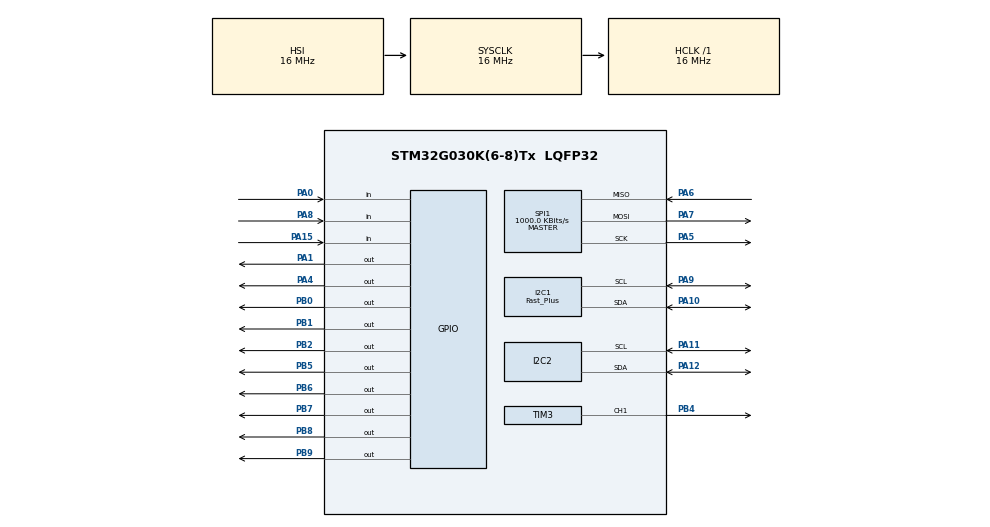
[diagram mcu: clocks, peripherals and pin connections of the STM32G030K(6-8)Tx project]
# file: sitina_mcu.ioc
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Dma.I2C1_RX.1.Direction=DMA_PERIPH_TO_MEMORY
Dma.I2C1_RX.1.EventEnable=DISABLE
Dma.I2C1_RX.1.Instance=DMA1_Channel2
Dma.I2C1_RX.1.MemDataAlignment=DMA_MDATAALIGN_BYTE
Dma.I2C1_RX.1.MemInc=DMA_MINC_ENABLE
Dma.I2C1_RX.1.Mode=DMA_NORMAL
Dma.I2C1_RX.1.PeriphDataAlignment=DMA_PDATAALIGN_BYTE
Dma.I2C1_RX.1.PeriphInc=DMA_PINC_DISABLE
Dma.I2C1_RX.1.Polarity=HAL_DMAMUX_REQ_GEN_RISING
Dma.I2C1_RX.1.Priority=DMA_PRIORITY_LOW
Dma.I2C1_RX.1.RequestNumber=1
Dma.I2C1_RX.1.SignalID=NONE
Dma.I2C1_RX.1.SyncEnable=DISABLE
Dma.I2C1_RX.1.SyncPolarity=HAL_DMAMUX_SYNC_NO_EVENT
Dma.I2C1_RX.1.SyncRequestNumber=1
Dma.I2C1_RX.1.SyncSignalID=NONE
Dma.I2C1_TX.2.Direction=DMA_MEMORY_TO_PERIPH
Dma.I2C1_TX.2.EventEnable=DISABLE
Dma.I2C1_TX.2.Instance=DMA1_Channel3
Dma.I2C1_TX.2.MemDataAlignment=DMA_MDATAALIGN_BYTE
Dma.I2C1_TX.2.MemInc=DMA_MINC_ENABLE
Dma.I2C1_TX.2.Mode=DMA_NORMAL
Dma.I2C1_TX.2.PeriphDataAlignment=DMA_PDATAALIGN_BYTE
Dma.I2C1_TX.2.PeriphInc=DMA_PINC_DISABLE
Dma.I2C1_TX.2.Polarity=HAL_DMAMUX_REQ_GEN_RISING
Dma.I2C1_TX.2.Priority=DMA_PRIORITY_LOW
Dma.I2C1_TX.2.RequestNumber=1
Dma.I2C1_TX.2.SignalID=NONE
Dma.I2C1_TX.2.SyncEnable=DISABLE
Dma.I2C1_TX.2.SyncPolarity=HAL_DMAMUX_SYNC_NO_EVENT
Dma.I2C1_TX.2.SyncRequestNumber=1
Dma.I2C1_TX.2.SyncSignalID=NONE
Dma.Request0=SPI1_TX
Dma.Request1=I2C1_RX
Dma.Request2=I2C1_TX
Dma.SPI1_TX.0.Direction=DMA_MEMORY_TO_PERIPH
Dma.SPI1_TX.0.EventEnable=DISABLE
Dma.SPI1_TX.0.Instance=DMA1_Channel1
Dma.SPI1_TX.0.MemDataAlignment=DMA_MDATAALIGN_BYTE
Dma.SPI1_TX.0.MemInc=DMA_MINC_ENABLE
Dma.SPI1_TX.0.Mode=DMA_NORMAL
Dma.SPI1_TX.0.PeriphDataAlignment=DMA_PDATAALIGN_BYTE
Dma.SPI1_TX.0.PeriphInc=DMA_PINC_DISABLE
Dma.SPI1_TX.0.Polarity=HAL_DMAMUX_REQ_GEN_RISING
Dma.SPI1_TX.0.Priority=DMA_PRIORITY_LOW
Dma.SPI1_TX.0.RequestNumber=1
Dma.SPI1_TX.0.SignalID=NONE
Dma.SPI1_TX.0.SyncEnable=DISABLE
Dma.SPI1_TX.0.SyncPolarity=HAL_DMAMUX_SYNC_NO_EVENT
Dma.SPI1_TX.0.SyncRequestNumber=1
Dma.SPI1_TX.0.SyncSignalID=NONE
I2C1.I2C_Speed_Mode=I2C_Fast_Plus
I2C1.OwnAddress=32
I2C1.Timing=0x00200105
I2C2.Timing=0x00503D58
Mcu.Family=STM32G0
Mcu.Name=STM32G030K(6-8)Tx
Mcu.Package=LQFP32
NVIC.DMA1_Channel1_IRQn=true\:0\:0\:false\:false\:true\:false\:true\:true
NVIC.DMA1_Channel2_3_IRQn=true\:0\:0\:false\:false\:true\:false\:true\:true
NVIC.I2C1_IRQn=true\:0\:0\:false\:false\:true\:true\:true\:true
NVIC.RTC_TAMP_IRQn=true\:0\:0\:false\:false\:true\:true\:true\:true
PA0.Signal=GPIO_Input
PA1.Signal=GPIO_Output
PA10.Mode=I2C
PA10.Signal=I2C1_SDA
PA11\ [PA9].Mode=I2C
PA11\ [PA9].Signal=I2C2_SCL
PA12\ [PA10].Mode=I2C
PA12\ [PA10].Signal=I2C2_SDA
PA13.Mode=Serial_Wire
PA13.Signal=SYS_SWDIO
PA14-BOOT0.Mode=Serial_Wire
PA14-BOOT0.Signal=SYS_SWCLK
PA15.Signal=GPIO_Input
PA2.Signal=USART2_TX
PA3.Signal=USART2_RX
PA4.Signal=GPIO_Output
PA5.Mode=Full_Duplex_Master
PA5.Signal=SPI1_SCK
PA6.Mode=Full_Duplex_Master
PA6.Signal=SPI1_MISO
PA7.Mode=Full_Duplex_Master
PA7.Signal=SPI1_MOSI
PA8.Signal=GPIO_Input
PA9.Mode=I2C
PA9.Signal=I2C1_SCL
PB0.Signal=GPIO_Output
PB1.Signal=GPIO_Output
PB2.Signal=GPIO_Output
PB3.Signal=S_TIM1_CH2
PB4.Signal=S_TIM3_CH1
PB5.Signal=GPIO_Output
PB6.Signal=GPIO_Output
PB7.Signal=GPIO_Output
PB8.Signal=GPIO_Output
PB9.Signal=GPIO_Output
PC14-OSC32_IN\ (PC14).Mode=LSE-External-Oscillator
PC14-OSC32_IN\ (PC14).Signal=RCC_OSC32_IN
PC15-OSC32_OUT\ (PC15).Mode=LSE-External-Oscillator
PC15-OSC32_OUT\ (PC15).Signal=RCC_OSC32_OUT
ProjectManager.HeapSize=0x200
ProjectManager.StackSize=0x400
ProjectManager.TargetToolchain=STM32CubeIDE
RCC.AHBFreq_Value=16000000
RCC.CortexFreq_Value=16000000
RCC.EXTERNAL_CLOCK_VALUE=12288000
RCC.HCLKFreq_Value=16000000
RCC.HSE_VALUE=8000000
RCC.HSI_VALUE=16000000
RCC.SYSCLKFreq_VALUE=16000000
RCC.VCOOutputFreq_Value=128000000
RTC.WakeUpCounter-WakeUp=68
SH.S_TIM1_CH2.0=TIM1_CH2
SH.S_TIM3_CH1.0=TIM3_CH1,PWM Generation1 CH1
SPI1.BaudRatePrescaler=SPI_BAUDRATEPRESCALER_16
SPI1.CalculateBaudRate=1000.0 KBits/s
SPI1.Direction=SPI_DIRECTION_2LINES
SPI1.Mode=SPI_MODE_MASTER
SPI1.NSSPMode=SPI_NSS_PULSE_DISABLE
SPI1.VirtualType=VM_MASTER
TIM3.Channel-PWM\ Generation1\ CH1=TIM_CHANNEL_1
TIM3.Period=255
VP_RTC_VS_RTC_Activate.Mode=RTC_Enabled
VP_RTC_VS_RTC_WakeUp_intern.Mode=WakeUp
board=custom

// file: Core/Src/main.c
/* USER CODE BEGIN Header */
/**
  ******************************************************************************
  * @file           : main.c
  * @brief          : Main program body
  ******************************************************************************
  * @attention
  *
  * Copyright (c) 2024 STMicroelectronics.
  * All rights reserved.
  *
  * This software is licensed under terms that can be found in the LICENSE file
  * in the root directory of this software component.
  * If no LICENSE file comes with this software, it is provided AS-IS.
  *
  ******************************************************************************
  */
/* USER CODE END Header */
#include "main.h"

/* USER CODE BEGIN Includes */
#include "app_main.h"
/* USER CODE END Includes */

I2C_HandleTypeDef hi2c1;
I2C_HandleTypeDef hi2c2;
DMA_HandleTypeDef hdma_i2c1_rx;
DMA_HandleTypeDef hdma_i2c1_tx;

RTC_HandleTypeDef hrtc;

SPI_HandleTypeDef hspi1;
DMA_HandleTypeDef hdma_spi1_tx;

TIM_HandleTypeDef htim3;

void SystemClock_Config(void);
static void MX_GPIO_Init(void);
static void MX_DMA_Init(void);
static void MX_I2C2_Init(void);
static void MX_TIM3_Init(void);
static void MX_SPI1_Init(void);
static void MX_RTC_Init(void);
static void MX_I2C1_Init(void);

int main(void)
{

  /* MCU Configuration--------------------------------------------------------*/

  /* Reset of all peripherals, Initializes the Flash interface and the Systick. */
  HAL_Init();

  /* Configure the system clock */
  SystemClock_Config();

  /* Initialize all configured peripherals */
  MX_GPIO_Init();
  MX_DMA_Init();
  MX_I2C2_Init();
  MX_TIM3_Init();
  MX_SPI1_Init();
  MX_RTC_Init();
  MX_I2C1_Init();
  /* USER CODE BEGIN 2 */
  app_init();
  /* USER CODE END 2 */

  /* Infinite loop */
  while (1)
  {

    /* USER CODE BEGIN 3 */
    app_tick();
  }
  /* USER CODE END 3 */
}

void SystemClock_Config(void)
{
  RCC_OscInitTypeDef RCC_OscInitStruct = {0};
  RCC_ClkInitTypeDef RCC_ClkInitStruct = {0};

  /** Configure the main internal regulator output voltage
  */
  HAL_PWREx_ControlVoltageScaling(PWR_REGULATOR_VOLTAGE_SCALE1);

  /** Initializes the RCC Oscillators according to the specified parameters
  * in the RCC_OscInitTypeDef structure.
  */
  RCC_OscInitStruct.OscillatorType = RCC_OSCILLATORTYPE_HSI|RCC_OSCILLATORTYPE_LSI;
  RCC_OscInitStruct.HSIState = RCC_HSI_ON;
  RCC_OscInitStruct.HSIDiv = RCC_HSI_DIV1;
  RCC_OscInitStruct.HSICalibrationValue = RCC_HSICALIBRATION_DEFAULT;
  RCC_OscInitStruct.LSIState = RCC_LSI_ON;
  RCC_OscInitStruct.PLL.PLLState = RCC_PLL_NONE;
  if (HAL_RCC_OscConfig(&RCC_OscInitStruct) != HAL_OK)
  {
    Error_Handler();
  }

  /** Initializes the CPU, AHB and APB buses clocks
  */
  RCC_ClkInitStruct.ClockType = RCC_CLOCKTYPE_HCLK|RCC_CLOCKTYPE_SYSCLK
                              |RCC_CLOCKTYPE_PCLK1;
  RCC_ClkInitStruct.SYSCLKSource = RCC_SYSCLKSOURCE_HSI;
  RCC_ClkInitStruct.AHBCLKDivider = RCC_SYSCLK_DIV1;
  RCC_ClkInitStruct.APB1CLKDivider = RCC_HCLK_DIV1;

  if (HAL_RCC_ClockConfig(&RCC_ClkInitStruct, FLASH_LATENCY_0) != HAL_OK)
  {
    Error_Handler();
  }
}

static void MX_I2C1_Init(void)
{

  hi2c1.Instance = I2C1;
  hi2c1.Init.Timing = 0x00200105;
  hi2c1.Init.OwnAddress1 = 64;
  hi2c1.Init.AddressingMode = I2C_ADDRESSINGMODE_7BIT;
  hi2c1.Init.DualAddressMode = I2C_DUALADDRESS_DISABLE;
  hi2c1.Init.OwnAddress2 = 0;
  hi2c1.Init.OwnAddress2Masks = I2C_OA2_NOMASK;
  hi2c1.Init.GeneralCallMode = I2C_GENERALCALL_DISABLE;
  hi2c1.Init.NoStretchMode = I2C_NOSTRETCH_DISABLE;
  if (HAL_I2C_Init(&hi2c1) != HAL_OK)
  {
    Error_Handler();
  }

  /** Configure Analogue filter
  */
  if (HAL_I2CEx_ConfigAnalogFilter(&hi2c1, I2C_ANALOGFILTER_ENABLE) != HAL_OK)
  {
    Error_Handler();
  }

  /** Configure Digital filter
  */
  if (HAL_I2CEx_ConfigDigitalFilter(&hi2c1, 0) != HAL_OK)
  {
    Error_Handler();
  }

  /** I2C Fast mode Plus enable
  */
  HAL_I2CEx_EnableFastModePlus(I2C_FASTMODEPLUS_I2C1);

}

static void MX_I2C2_Init(void)
{

  hi2c2.Instance = I2C2;
  hi2c2.Init.Timing = 0x00503D58;
  hi2c2.Init.OwnAddress1 = 0;
  hi2c2.Init.AddressingMode = I2C_ADDRESSINGMODE_7BIT;
  hi2c2.Init.DualAddressMode = I2C_DUALADDRESS_DISABLE;
  hi2c2.Init.OwnAddress2 = 0;
  hi2c2.Init.OwnAddress2Masks = I2C_OA2_NOMASK;
  hi2c2.Init.GeneralCallMode = I2C_GENERALCALL_DISABLE;
  hi2c2.Init.NoStretchMode = I2C_NOSTRETCH_DISABLE;
  if (HAL_I2C_Init(&hi2c2) != HAL_OK)
  {
    Error_Handler();
  }

  /** Configure Analogue filter
  */
  if (HAL_I2CEx_ConfigAnalogFilter(&hi2c2, I2C_ANALOGFILTER_ENABLE) != HAL_OK)
  {
    Error_Handler();
  }

  /** Configure Digital filter
  */
  if (HAL_I2CEx_ConfigDigitalFilter(&hi2c2, 0) != HAL_OK)
  {
    Error_Handler();
  }

}

static void MX_RTC_Init(void)
{

  /** Initialize RTC Only
  */
  hrtc.Instance = RTC;
  hrtc.Init.HourFormat = RTC_HOURFORMAT_24;
  hrtc.Init.AsynchPrediv = 127;
  hrtc.Init.SynchPrediv = 255;
  hrtc.Init.OutPut = RTC_OUTPUT_DISABLE;
  hrtc.Init.OutPutRemap = RTC_OUTPUT_REMAP_NONE;
  hrtc.Init.OutPutPolarity = RTC_OUTPUT_POLARITY_HIGH;
  hrtc.Init.OutPutType = RTC_OUTPUT_TYPE_OPENDRAIN;
  hrtc.Init.OutPutPullUp = RTC_OUTPUT_PULLUP_NONE;
  if (HAL_RTC_Init(&hrtc) != HAL_OK)
  {
    Error_Handler();
  }

  /** Enable the WakeUp
  */
  if (HAL_RTCEx_SetWakeUpTimer_IT(&hrtc, 68, RTC_WAKEUPCLOCK_RTCCLK_DIV16) != HAL_OK)
  {
    Error_Handler();
  }

}

static void MX_SPI1_Init(void)
{

  /* SPI1 parameter configuration*/
  hspi1.Instance = SPI1;
  hspi1.Init.Mode = SPI_MODE_MASTER;
  hspi1.Init.Direction = SPI_DIRECTION_2LINES;
  hspi1.Init.DataSize = SPI_DATASIZE_8BIT;
  hspi1.Init.CLKPolarity = SPI_POLARITY_LOW;
  hspi1.Init.CLKPhase = SPI_PHASE_1EDGE;
  hspi1.Init.NSS = SPI_NSS_SOFT;
  hspi1.Init.BaudRatePrescaler = SPI_BAUDRATEPRESCALER_16;
  hspi1.Init.FirstBit = SPI_FIRSTBIT_MSB;
  hspi1.Init.TIMode = SPI_TIMODE_DISABLE;
  hspi1.Init.CRCCalculation = SPI_CRCCALCULATION_DISABLE;
  hspi1.Init.CRCPolynomial = 7;
  hspi1.Init.CRCLength = SPI_CRC_LENGTH_DATASIZE;
  hspi1.Init.NSSPMode = SPI_NSS_PULSE_DISABLE;
  if (HAL_SPI_Init(&hspi1) != HAL_OK)
  {
    Error_Handler();
  }

}

static void MX_TIM3_Init(void)
{

  TIM_MasterConfigTypeDef sMasterConfig = {0};
  TIM_OC_InitTypeDef sConfigOC = {0};

  htim3.Instance = TIM3;
  htim3.Init.Prescaler = 0;
  htim3.Init.CounterMode = TIM_COUNTERMODE_UP;
  htim3.Init.Period = 255;
  htim3.Init.ClockDivision = TIM_CLOCKDIVISION_DIV1;
  htim3.Init.AutoReloadPreload = TIM_AUTORELOAD_PRELOAD_DISABLE;
  if (HAL_TIM_PWM_Init(&htim3) != HAL_OK)
  {
    Error_Handler();
  }
  sMasterConfig.MasterOutputTrigger = TIM_TRGO_RESET;
  sMasterConfig.MasterSlaveMode = TIM_MASTERSLAVEMODE_DISABLE;
  if (HAL_TIMEx_MasterConfigSynchronization(&htim3, &sMasterConfig) != HAL_OK)
  {
    Error_Handler();
  }
  sConfigOC.OCMode = TIM_OCMODE_PWM1;
  sConfigOC.Pulse = 0;
  sConfigOC.OCPolarity = TIM_OCPOLARITY_HIGH;
  sConfigOC.OCFastMode = TIM_OCFAST_DISABLE;
  if (HAL_TIM_PWM_ConfigChannel(&htim3, &sConfigOC, TIM_CHANNEL_1) != HAL_OK)
  {
    Error_Handler();
  }
  HAL_TIM_MspPostInit(&htim3);

}

static void MX_DMA_Init(void)
{

  /* DMA controller clock enable */
  __HAL_RCC_DMA1_CLK_ENABLE();

  /* DMA interrupt init */
  /* DMA1_Channel1_IRQn interrupt configuration */
  HAL_NVIC_SetPriority(DMA1_Channel1_IRQn, 0, 0);
  HAL_NVIC_EnableIRQ(DMA1_Channel1_IRQn);
  /* DMA1_Channel2_3_IRQn interrupt configuration */
  HAL_NVIC_SetPriority(DMA1_Channel2_3_IRQn, 0, 0);
  HAL_NVIC_EnableIRQ(DMA1_Channel2_3_IRQn);

}

static void MX_GPIO_Init(void)
{
  GPIO_InitTypeDef GPIO_InitStruct = {0};

  /* GPIO Ports Clock Enable */
  __HAL_RCC_GPIOB_CLK_ENABLE();
  __HAL_RCC_GPIOC_CLK_ENABLE();
  __HAL_RCC_GPIOA_CLK_ENABLE();

  /*Configure GPIO pin Output Level */
  HAL_GPIO_WritePin(GPIOB, GPIO_PIN_9|GPIO_PIN_0|GPIO_PIN_1|GPIO_PIN_2
                          |GPIO_PIN_5|GPIO_PIN_6|GPIO_PIN_7|GPIO_PIN_8, GPIO_PIN_RESET);

  /*Configure GPIO pin Output Level */
  HAL_GPIO_WritePin(GPIOA, GPIO_PIN_1|GPIO_PIN_4, GPIO_PIN_RESET);

  /*Configure GPIO pins : PB9 PB0 PB1 PB2
                           PB5 PB6 PB7 PB8 */
  GPIO_InitStruct.Pin = GPIO_PIN_9|GPIO_PIN_0|GPIO_PIN_1|GPIO_PIN_2
                          |GPIO_PIN_5|GPIO_PIN_6|GPIO_PIN_7|GPIO_PIN_8;
  GPIO_InitStruct.Mode = GPIO_MODE_OUTPUT_PP;
  GPIO_InitStruct.Pull = GPIO_NOPULL;
  GPIO_InitStruct.Speed = GPIO_SPEED_FREQ_LOW;
  HAL_GPIO_Init(GPIOB, &GPIO_InitStruct);

  /*Configure GPIO pins : PA0 PA8 PA15 */
  GPIO_InitStruct.Pin = GPIO_PIN_0|GPIO_PIN_8|GPIO_PIN_15;
  GPIO_InitStruct.Mode = GPIO_MODE_INPUT;
  GPIO_InitStruct.Pull = GPIO_NOPULL;
  HAL_GPIO_Init(GPIOA, &GPIO_InitStruct);

  /*Configure GPIO pins : PA1 PA4 */
  GPIO_InitStruct.Pin = GPIO_PIN_1|GPIO_PIN_4;
  GPIO_InitStruct.Mode = GPIO_MODE_OUTPUT_PP;
  GPIO_InitStruct.Pull = GPIO_NOPULL;
  GPIO_InitStruct.Speed = GPIO_SPEED_FREQ_LOW;
  HAL_GPIO_Init(GPIOA, &GPIO_InitStruct);

  /*Configure GPIO pins : PA2 PA3 */
  GPIO_InitStruct.Pin = GPIO_PIN_2|GPIO_PIN_3;
  GPIO_InitStruct.Mode = GPIO_MODE_AF_PP;
  GPIO_InitStruct.Pull = GPIO_NOPULL;
  GPIO_InitStruct.Speed = GPIO_SPEED_FREQ_LOW;
  GPIO_InitStruct.Alternate = GPIO_AF1_USART2;
  HAL_GPIO_Init(GPIOA, &GPIO_InitStruct);

  /*Configure GPIO pin : PB3 */
  GPIO_InitStruct.Pin = GPIO_PIN_3;
  GPIO_InitStruct.Mode = GPIO_MODE_AF_PP;
  GPIO_InitStruct.Pull = GPIO_NOPULL;
  GPIO_InitStruct.Speed = GPIO_SPEED_FREQ_LOW;
  GPIO_InitStruct.Alternate = GPIO_AF1_TIM1;
  HAL_GPIO_Init(GPIOB, &GPIO_InitStruct);

}

void Error_Handler(void)
{
  __disable_irq();
  while (1)
  {
  }
}
